VERSION 5.8 ;
BUSBITCHARS "[]" ;
DIVIDERCHAR "/" ;
UNITS
    DATABASE MICRONS 1000 ;
END UNITS

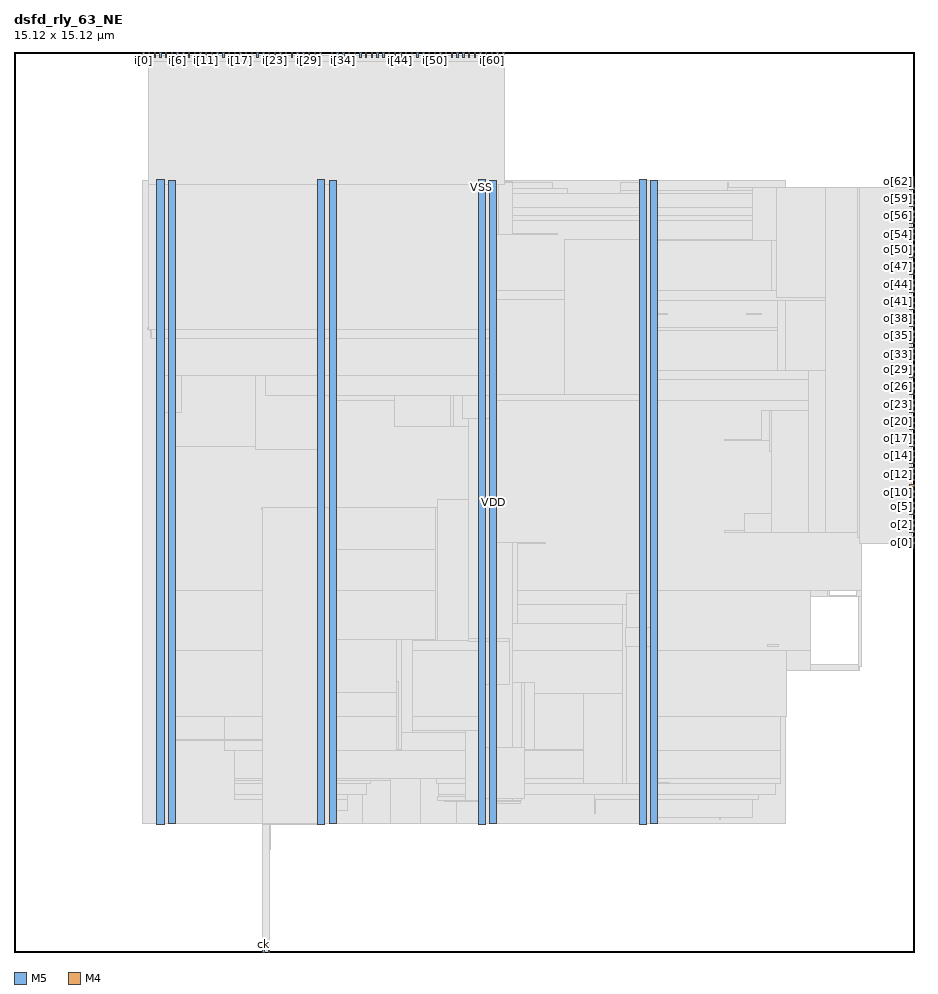
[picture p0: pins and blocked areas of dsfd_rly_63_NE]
MACRO dsfd_rly_63_NE
  FOREIGN dsfd_rly_63_NE 0 0 ;
  CLASS BLOCK ;
  SIZE 15.12 BY 15.12 ;
  PIN ck
    DIRECTION INPUT ;
    USE SIGNAL ;
    PORT
      LAYER M5 ;
        RECT  4.176 0 4.2 0.084 ;
    END
  END ck
  PIN i[0]
    DIRECTION INPUT ;
    USE SIGNAL ;
    PORT
      LAYER M5 ;
        RECT  2.16 15.036 2.184 15.12 ;
    END
  END i[0]
  PIN i[10]
    DIRECTION INPUT ;
    USE SIGNAL ;
    PORT
      LAYER M5 ;
        RECT  3.12 15.036 3.144 15.12 ;
    END
  END i[10]
  PIN i[11]
    DIRECTION INPUT ;
    USE SIGNAL ;
    PORT
      LAYER M5 ;
        RECT  3.216 15.036 3.24 15.12 ;
    END
  END i[11]
  PIN i[12]
    DIRECTION INPUT ;
    USE SIGNAL ;
    PORT
      LAYER M5 ;
        RECT  3.312 15.036 3.336 15.12 ;
    END
  END i[12]
  PIN i[13]
    DIRECTION INPUT ;
    USE SIGNAL ;
    PORT
      LAYER M5 ;
        RECT  3.408 15.036 3.432 15.12 ;
    END
  END i[13]
  PIN i[14]
    DIRECTION INPUT ;
    USE SIGNAL ;
    PORT
      LAYER M5 ;
        RECT  3.504 15.036 3.528 15.12 ;
    END
  END i[14]
  PIN i[15]
    DIRECTION INPUT ;
    USE SIGNAL ;
    PORT
      LAYER M5 ;
        RECT  3.6 15.036 3.624 15.12 ;
    END
  END i[15]
  PIN i[16]
    DIRECTION INPUT ;
    USE SIGNAL ;
    PORT
      LAYER M5 ;
        RECT  3.696 15.036 3.72 15.12 ;
    END
  END i[16]
  PIN i[17]
    DIRECTION INPUT ;
    USE SIGNAL ;
    PORT
      LAYER M5 ;
        RECT  3.792 15.036 3.816 15.12 ;
    END
  END i[17]
  PIN i[18]
    DIRECTION INPUT ;
    USE SIGNAL ;
    PORT
      LAYER M5 ;
        RECT  3.888 15.036 3.912 15.12 ;
    END
  END i[18]
  PIN i[19]
    DIRECTION INPUT ;
    USE SIGNAL ;
    PORT
      LAYER M5 ;
        RECT  3.984 15.036 4.008 15.12 ;
    END
  END i[19]
  PIN i[1]
    DIRECTION INPUT ;
    USE SIGNAL ;
    PORT
      LAYER M5 ;
        RECT  2.256 15.036 2.28 15.12 ;
    END
  END i[1]
  PIN i[20]
    DIRECTION INPUT ;
    USE SIGNAL ;
    PORT
      LAYER M5 ;
        RECT  4.08 15.036 4.104 15.12 ;
    END
  END i[20]
  PIN i[21]
    DIRECTION INPUT ;
    USE SIGNAL ;
    PORT
      LAYER M5 ;
        RECT  4.176 15.036 4.2 15.12 ;
    END
  END i[21]
  PIN i[22]
    DIRECTION INPUT ;
    USE SIGNAL ;
    PORT
      LAYER M5 ;
        RECT  4.272 15.036 4.296 15.12 ;
    END
  END i[22]
  PIN i[23]
    DIRECTION INPUT ;
    USE SIGNAL ;
    PORT
      LAYER M5 ;
        RECT  4.368 15.036 4.392 15.12 ;
    END
  END i[23]
  PIN i[24]
    DIRECTION INPUT ;
    USE SIGNAL ;
    PORT
      LAYER M5 ;
        RECT  4.464 15.036 4.488 15.12 ;
    END
  END i[24]
  PIN i[25]
    DIRECTION INPUT ;
    USE SIGNAL ;
    PORT
      LAYER M5 ;
        RECT  4.56 15.036 4.584 15.12 ;
    END
  END i[25]
  PIN i[26]
    DIRECTION INPUT ;
    USE SIGNAL ;
    PORT
      LAYER M5 ;
        RECT  4.656 15.036 4.68 15.12 ;
    END
  END i[26]
  PIN i[27]
    DIRECTION INPUT ;
    USE SIGNAL ;
    PORT
      LAYER M5 ;
        RECT  4.752 15.036 4.776 15.12 ;
    END
  END i[27]
  PIN i[28]
    DIRECTION INPUT ;
    USE SIGNAL ;
    PORT
      LAYER M5 ;
        RECT  4.848 15.036 4.872 15.12 ;
    END
  END i[28]
  PIN i[29]
    DIRECTION INPUT ;
    USE SIGNAL ;
    PORT
      LAYER M5 ;
        RECT  4.944 15.036 4.968 15.12 ;
    END
  END i[29]
  PIN i[2]
    DIRECTION INPUT ;
    USE SIGNAL ;
    PORT
      LAYER M5 ;
        RECT  2.352 15.036 2.376 15.12 ;
    END
  END i[2]
  PIN i[30]
    DIRECTION INPUT ;
    USE SIGNAL ;
    PORT
      LAYER M5 ;
        RECT  5.04 15.036 5.064 15.12 ;
    END
  END i[30]
  PIN i[31]
    DIRECTION INPUT ;
    USE SIGNAL ;
    PORT
      LAYER M5 ;
        RECT  5.136 15.036 5.16 15.12 ;
    END
  END i[31]
  PIN i[32]
    DIRECTION INPUT ;
    USE SIGNAL ;
    PORT
      LAYER M5 ;
        RECT  5.328 15.036 5.352 15.12 ;
    END
  END i[32]
  PIN i[33]
    DIRECTION INPUT ;
    USE SIGNAL ;
    PORT
      LAYER M5 ;
        RECT  5.424 15.036 5.448 15.12 ;
    END
  END i[33]
  PIN i[34]
    DIRECTION INPUT ;
    USE SIGNAL ;
    PORT
      LAYER M5 ;
        RECT  5.52 15.036 5.544 15.12 ;
    END
  END i[34]
  PIN i[35]
    DIRECTION INPUT ;
    USE SIGNAL ;
    PORT
      LAYER M5 ;
        RECT  5.616 15.036 5.64 15.12 ;
    END
  END i[35]
  PIN i[36]
    DIRECTION INPUT ;
    USE SIGNAL ;
    PORT
      LAYER M5 ;
        RECT  5.712 15.036 5.736 15.12 ;
    END
  END i[36]
  PIN i[37]
    DIRECTION INPUT ;
    USE SIGNAL ;
    PORT
      LAYER M5 ;
        RECT  5.808 15.036 5.832 15.12 ;
    END
  END i[37]
  PIN i[38]
    DIRECTION INPUT ;
    USE SIGNAL ;
    PORT
      LAYER M5 ;
        RECT  5.904 15.036 5.928 15.12 ;
    END
  END i[38]
  PIN i[39]
    DIRECTION INPUT ;
    USE SIGNAL ;
    PORT
      LAYER M5 ;
        RECT  6 15.036 6.024 15.12 ;
    END
  END i[39]
  PIN i[3]
    DIRECTION INPUT ;
    USE SIGNAL ;
    PORT
      LAYER M5 ;
        RECT  2.448 15.036 2.472 15.12 ;
    END
  END i[3]
  PIN i[40]
    DIRECTION INPUT ;
    USE SIGNAL ;
    PORT
      LAYER M5 ;
        RECT  6.096 15.036 6.12 15.12 ;
    END
  END i[40]
  PIN i[41]
    DIRECTION INPUT ;
    USE SIGNAL ;
    PORT
      LAYER M5 ;
        RECT  6.192 15.036 6.216 15.12 ;
    END
  END i[41]
  PIN i[42]
    DIRECTION INPUT ;
    USE SIGNAL ;
    PORT
      LAYER M5 ;
        RECT  6.288 15.036 6.312 15.12 ;
    END
  END i[42]
  PIN i[43]
    DIRECTION INPUT ;
    USE SIGNAL ;
    PORT
      LAYER M5 ;
        RECT  6.384 15.036 6.408 15.12 ;
    END
  END i[43]
  PIN i[44]
    DIRECTION INPUT ;
    USE SIGNAL ;
    PORT
      LAYER M5 ;
        RECT  6.48 15.036 6.504 15.12 ;
    END
  END i[44]
  PIN i[45]
    DIRECTION INPUT ;
    USE SIGNAL ;
    PORT
      LAYER M5 ;
        RECT  6.576 15.036 6.6 15.12 ;
    END
  END i[45]
  PIN i[46]
    DIRECTION INPUT ;
    USE SIGNAL ;
    PORT
      LAYER M5 ;
        RECT  6.672 15.036 6.696 15.12 ;
    END
  END i[46]
  PIN i[47]
    DIRECTION INPUT ;
    USE SIGNAL ;
    PORT
      LAYER M5 ;
        RECT  6.768 15.036 6.792 15.12 ;
    END
  END i[47]
  PIN i[48]
    DIRECTION INPUT ;
    USE SIGNAL ;
    PORT
      LAYER M5 ;
        RECT  6.864 15.036 6.888 15.12 ;
    END
  END i[48]
  PIN i[49]
    DIRECTION INPUT ;
    USE SIGNAL ;
    PORT
      LAYER M5 ;
        RECT  6.96 15.036 6.984 15.12 ;
    END
  END i[49]
  PIN i[4]
    DIRECTION INPUT ;
    USE SIGNAL ;
    PORT
      LAYER M5 ;
        RECT  2.544 15.036 2.568 15.12 ;
    END
  END i[4]
  PIN i[50]
    DIRECTION INPUT ;
    USE SIGNAL ;
    PORT
      LAYER M5 ;
        RECT  7.056 15.036 7.08 15.12 ;
    END
  END i[50]
  PIN i[51]
    DIRECTION INPUT ;
    USE SIGNAL ;
    PORT
      LAYER M5 ;
        RECT  7.152 15.036 7.176 15.12 ;
    END
  END i[51]
  PIN i[52]
    DIRECTION INPUT ;
    USE SIGNAL ;
    PORT
      LAYER M5 ;
        RECT  7.248 15.036 7.272 15.12 ;
    END
  END i[52]
  PIN i[53]
    DIRECTION INPUT ;
    USE SIGNAL ;
    PORT
      LAYER M5 ;
        RECT  7.344 15.036 7.368 15.12 ;
    END
  END i[53]
  PIN i[54]
    DIRECTION INPUT ;
    USE SIGNAL ;
    PORT
      LAYER M5 ;
        RECT  7.44 15.036 7.464 15.12 ;
    END
  END i[54]
  PIN i[55]
    DIRECTION INPUT ;
    USE SIGNAL ;
    PORT
      LAYER M5 ;
        RECT  7.536 15.036 7.56 15.12 ;
    END
  END i[55]
  PIN i[56]
    DIRECTION INPUT ;
    USE SIGNAL ;
    PORT
      LAYER M5 ;
        RECT  7.632 15.036 7.656 15.12 ;
    END
  END i[56]
  PIN i[57]
    DIRECTION INPUT ;
    USE SIGNAL ;
    PORT
      LAYER M5 ;
        RECT  7.728 15.036 7.752 15.12 ;
    END
  END i[57]
  PIN i[58]
    DIRECTION INPUT ;
    USE SIGNAL ;
    PORT
      LAYER M5 ;
        RECT  7.824 15.036 7.848 15.12 ;
    END
  END i[58]
  PIN i[59]
    DIRECTION INPUT ;
    USE SIGNAL ;
    PORT
      LAYER M5 ;
        RECT  7.92 15.036 7.944 15.12 ;
    END
  END i[59]
  PIN i[5]
    DIRECTION INPUT ;
    USE SIGNAL ;
    PORT
      LAYER M5 ;
        RECT  2.64 15.036 2.664 15.12 ;
    END
  END i[5]
  PIN i[60]
    DIRECTION INPUT ;
    USE SIGNAL ;
    PORT
      LAYER M5 ;
        RECT  8.016 15.036 8.04 15.12 ;
    END
  END i[60]
  PIN i[61]
    DIRECTION INPUT ;
    USE SIGNAL ;
    PORT
      LAYER M5 ;
        RECT  8.112 15.036 8.136 15.12 ;
    END
  END i[61]
  PIN i[62]
    DIRECTION INPUT ;
    USE SIGNAL ;
    PORT
      LAYER M5 ;
        RECT  8.208 15.036 8.232 15.12 ;
    END
  END i[62]
  PIN i[6]
    DIRECTION INPUT ;
    USE SIGNAL ;
    PORT
      LAYER M5 ;
        RECT  2.736 15.036 2.76 15.12 ;
    END
  END i[6]
  PIN i[7]
    DIRECTION INPUT ;
    USE SIGNAL ;
    PORT
      LAYER M5 ;
        RECT  2.832 15.036 2.856 15.12 ;
    END
  END i[7]
  PIN i[8]
    DIRECTION INPUT ;
    USE SIGNAL ;
    PORT
      LAYER M5 ;
        RECT  2.928 15.036 2.952 15.12 ;
    END
  END i[8]
  PIN i[9]
    DIRECTION INPUT ;
    USE SIGNAL ;
    PORT
      LAYER M5 ;
        RECT  3.024 15.036 3.048 15.12 ;
    END
  END i[9]
  PIN o[0]
    DIRECTION OUTPUT ;
    USE SIGNAL ;
    PORT
      LAYER M4 ;
        RECT  15.036 6.864 15.12 6.888 ;
    END
  END o[0]
  PIN o[10]
    DIRECTION OUTPUT ;
    USE SIGNAL ;
    PORT
      LAYER M4 ;
        RECT  15.036 7.824 15.12 7.848 ;
    END
  END o[10]
  PIN o[11]
    DIRECTION OUTPUT ;
    USE SIGNAL ;
    PORT
      LAYER M4 ;
        RECT  15.036 7.92 15.12 7.944 ;
    END
  END o[11]
  PIN o[12]
    DIRECTION OUTPUT ;
    USE SIGNAL ;
    PORT
      LAYER M4 ;
        RECT  15.036 8.016 15.12 8.04 ;
    END
  END o[12]
  PIN o[13]
    DIRECTION OUTPUT ;
    USE SIGNAL ;
    PORT
      LAYER M4 ;
        RECT  15.036 8.112 15.12 8.136 ;
    END
  END o[13]
  PIN o[14]
    DIRECTION OUTPUT ;
    USE SIGNAL ;
    PORT
      LAYER M4 ;
        RECT  15.036 8.208 15.12 8.232 ;
    END
  END o[14]
  PIN o[15]
    DIRECTION OUTPUT ;
    USE SIGNAL ;
    PORT
      LAYER M4 ;
        RECT  15.036 8.304 15.12 8.328 ;
    END
  END o[15]
  PIN o[16]
    DIRECTION OUTPUT ;
    USE SIGNAL ;
    PORT
      LAYER M4 ;
        RECT  15.036 8.4 15.12 8.424 ;
    END
  END o[16]
  PIN o[17]
    DIRECTION OUTPUT ;
    USE SIGNAL ;
    PORT
      LAYER M4 ;
        RECT  15.036 8.496 15.12 8.52 ;
    END
  END o[17]
  PIN o[18]
    DIRECTION OUTPUT ;
    USE SIGNAL ;
    PORT
      LAYER M4 ;
        RECT  15.036 8.592 15.12 8.616 ;
    END
  END o[18]
  PIN o[19]
    DIRECTION OUTPUT ;
    USE SIGNAL ;
    PORT
      LAYER M4 ;
        RECT  15.036 8.688 15.12 8.712 ;
    END
  END o[19]
  PIN o[1]
    DIRECTION OUTPUT ;
    USE SIGNAL ;
    PORT
      LAYER M4 ;
        RECT  15.036 6.96 15.12 6.984 ;
    END
  END o[1]
  PIN o[20]
    DIRECTION OUTPUT ;
    USE SIGNAL ;
    PORT
      LAYER M4 ;
        RECT  15.036 8.784 15.12 8.808 ;
    END
  END o[20]
  PIN o[21]
    DIRECTION OUTPUT ;
    USE SIGNAL ;
    PORT
      LAYER M4 ;
        RECT  15.036 8.88 15.12 8.904 ;
    END
  END o[21]
  PIN o[22]
    DIRECTION OUTPUT ;
    USE SIGNAL ;
    PORT
      LAYER M4 ;
        RECT  15.036 8.976 15.12 9 ;
    END
  END o[22]
  PIN o[23]
    DIRECTION OUTPUT ;
    USE SIGNAL ;
    PORT
      LAYER M4 ;
        RECT  15.036 9.072 15.12 9.096 ;
    END
  END o[23]
  PIN o[24]
    DIRECTION OUTPUT ;
    USE SIGNAL ;
    PORT
      LAYER M4 ;
        RECT  15.036 9.168 15.12 9.192 ;
    END
  END o[24]
  PIN o[25]
    DIRECTION OUTPUT ;
    USE SIGNAL ;
    PORT
      LAYER M4 ;
        RECT  15.036 9.264 15.12 9.288 ;
    END
  END o[25]
  PIN o[26]
    DIRECTION OUTPUT ;
    USE SIGNAL ;
    PORT
      LAYER M4 ;
        RECT  15.036 9.36 15.12 9.384 ;
    END
  END o[26]
  PIN o[27]
    DIRECTION OUTPUT ;
    USE SIGNAL ;
    PORT
      LAYER M4 ;
        RECT  15.036 9.456 15.12 9.48 ;
    END
  END o[27]
  PIN o[28]
    DIRECTION OUTPUT ;
    USE SIGNAL ;
    PORT
      LAYER M4 ;
        RECT  15.036 9.552 15.12 9.576 ;
    END
  END o[28]
  PIN o[29]
    DIRECTION OUTPUT ;
    USE SIGNAL ;
    PORT
      LAYER M4 ;
        RECT  15.036 9.648 15.12 9.672 ;
    END
  END o[29]
  PIN o[2]
    DIRECTION OUTPUT ;
    USE SIGNAL ;
    PORT
      LAYER M4 ;
        RECT  15.036 7.056 15.12 7.08 ;
    END
  END o[2]
  PIN o[30]
    DIRECTION OUTPUT ;
    USE SIGNAL ;
    PORT
      LAYER M4 ;
        RECT  15.036 9.744 15.12 9.768 ;
    END
  END o[30]
  PIN o[31]
    DIRECTION OUTPUT ;
    USE SIGNAL ;
    PORT
      LAYER M4 ;
        RECT  15.036 9.84 15.12 9.864 ;
    END
  END o[31]
  PIN o[32]
    DIRECTION OUTPUT ;
    USE SIGNAL ;
    PORT
      LAYER M4 ;
        RECT  15.036 9.936 15.12 9.96 ;
    END
  END o[32]
  PIN o[33]
    DIRECTION OUTPUT ;
    USE SIGNAL ;
    PORT
      LAYER M4 ;
        RECT  15.036 10.032 15.12 10.056 ;
    END
  END o[33]
  PIN o[34]
    DIRECTION OUTPUT ;
    USE SIGNAL ;
    PORT
      LAYER M4 ;
        RECT  15.036 10.128 15.12 10.152 ;
    END
  END o[34]
  PIN o[35]
    DIRECTION OUTPUT ;
    USE SIGNAL ;
    PORT
      LAYER M4 ;
        RECT  15.036 10.224 15.12 10.248 ;
    END
  END o[35]
  PIN o[36]
    DIRECTION OUTPUT ;
    USE SIGNAL ;
    PORT
      LAYER M4 ;
        RECT  15.036 10.32 15.12 10.344 ;
    END
  END o[36]
  PIN o[37]
    DIRECTION OUTPUT ;
    USE SIGNAL ;
    PORT
      LAYER M4 ;
        RECT  15.036 10.416 15.12 10.44 ;
    END
  END o[37]
  PIN o[38]
    DIRECTION OUTPUT ;
    USE SIGNAL ;
    PORT
      LAYER M4 ;
        RECT  15.036 10.512 15.12 10.536 ;
    END
  END o[38]
  PIN o[39]
    DIRECTION OUTPUT ;
    USE SIGNAL ;
    PORT
      LAYER M4 ;
        RECT  15.036 10.608 15.12 10.632 ;
    END
  END o[39]
  PIN o[3]
    DIRECTION OUTPUT ;
    USE SIGNAL ;
    PORT
      LAYER M4 ;
        RECT  15.036 7.152 15.12 7.176 ;
    END
  END o[3]
  PIN o[40]
    DIRECTION OUTPUT ;
    USE SIGNAL ;
    PORT
      LAYER M4 ;
        RECT  15.036 10.704 15.12 10.728 ;
    END
  END o[40]
  PIN o[41]
    DIRECTION OUTPUT ;
    USE SIGNAL ;
    PORT
      LAYER M4 ;
        RECT  15.036 10.8 15.12 10.824 ;
    END
  END o[41]
  PIN o[42]
    DIRECTION OUTPUT ;
    USE SIGNAL ;
    PORT
      LAYER M4 ;
        RECT  15.036 10.896 15.12 10.92 ;
    END
  END o[42]
  PIN o[43]
    DIRECTION OUTPUT ;
    USE SIGNAL ;
    PORT
      LAYER M4 ;
        RECT  15.036 10.992 15.12 11.016 ;
    END
  END o[43]
  PIN o[44]
    DIRECTION OUTPUT ;
    USE SIGNAL ;
    PORT
      LAYER M4 ;
        RECT  15.036 11.088 15.12 11.112 ;
    END
  END o[44]
  PIN o[45]
    DIRECTION OUTPUT ;
    USE SIGNAL ;
    PORT
      LAYER M4 ;
        RECT  15.036 11.184 15.12 11.208 ;
    END
  END o[45]
  PIN o[46]
    DIRECTION OUTPUT ;
    USE SIGNAL ;
    PORT
      LAYER M4 ;
        RECT  15.036 11.28 15.12 11.304 ;
    END
  END o[46]
  PIN o[47]
    DIRECTION OUTPUT ;
    USE SIGNAL ;
    PORT
      LAYER M4 ;
        RECT  15.036 11.376 15.12 11.4 ;
    END
  END o[47]
  PIN o[48]
    DIRECTION OUTPUT ;
    USE SIGNAL ;
    PORT
      LAYER M4 ;
        RECT  15.036 11.472 15.12 11.496 ;
    END
  END o[48]
  PIN o[49]
    DIRECTION OUTPUT ;
    USE SIGNAL ;
    PORT
      LAYER M4 ;
        RECT  15.036 11.568 15.12 11.592 ;
    END
  END o[49]
  PIN o[4]
    DIRECTION OUTPUT ;
    USE SIGNAL ;
    PORT
      LAYER M4 ;
        RECT  15.036 7.248 15.12 7.272 ;
    END
  END o[4]
  PIN o[50]
    DIRECTION OUTPUT ;
    USE SIGNAL ;
    PORT
      LAYER M4 ;
        RECT  15.036 11.664 15.12 11.688 ;
    END
  END o[50]
  PIN o[51]
    DIRECTION OUTPUT ;
    USE SIGNAL ;
    PORT
      LAYER M4 ;
        RECT  15.036 11.76 15.12 11.784 ;
    END
  END o[51]
  PIN o[52]
    DIRECTION OUTPUT ;
    USE SIGNAL ;
    PORT
      LAYER M4 ;
        RECT  15.036 11.856 15.12 11.88 ;
    END
  END o[52]
  PIN o[53]
    DIRECTION OUTPUT ;
    USE SIGNAL ;
    PORT
      LAYER M4 ;
        RECT  15.036 11.952 15.12 11.976 ;
    END
  END o[53]
  PIN o[54]
    DIRECTION OUTPUT ;
    USE SIGNAL ;
    PORT
      LAYER M4 ;
        RECT  15.036 12.048 15.12 12.072 ;
    END
  END o[54]
  PIN o[55]
    DIRECTION OUTPUT ;
    USE SIGNAL ;
    PORT
      LAYER M4 ;
        RECT  15.036 12.144 15.12 12.168 ;
    END
  END o[55]
  PIN o[56]
    DIRECTION OUTPUT ;
    USE SIGNAL ;
    PORT
      LAYER M4 ;
        RECT  15.036 12.24 15.12 12.264 ;
    END
  END o[56]
  PIN o[57]
    DIRECTION OUTPUT ;
    USE SIGNAL ;
    PORT
      LAYER M4 ;
        RECT  15.036 12.336 15.12 12.36 ;
    END
  END o[57]
  PIN o[58]
    DIRECTION OUTPUT ;
    USE SIGNAL ;
    PORT
      LAYER M4 ;
        RECT  15.036 12.432 15.12 12.456 ;
    END
  END o[58]
  PIN o[59]
    DIRECTION OUTPUT ;
    USE SIGNAL ;
    PORT
      LAYER M4 ;
        RECT  15.036 12.528 15.12 12.552 ;
    END
  END o[59]
  PIN o[5]
    DIRECTION OUTPUT ;
    USE SIGNAL ;
    PORT
      LAYER M4 ;
        RECT  15.036 7.344 15.12 7.368 ;
    END
  END o[5]
  PIN o[60]
    DIRECTION OUTPUT ;
    USE SIGNAL ;
    PORT
      LAYER M4 ;
        RECT  15.036 12.624 15.12 12.648 ;
    END
  END o[60]
  PIN o[61]
    DIRECTION OUTPUT ;
    USE SIGNAL ;
    PORT
      LAYER M4 ;
        RECT  15.036 12.72 15.12 12.744 ;
    END
  END o[61]
  PIN o[62]
    DIRECTION OUTPUT ;
    USE SIGNAL ;
    PORT
      LAYER M4 ;
        RECT  15.036 12.816 15.12 12.84 ;
    END
  END o[62]
  PIN o[6]
    DIRECTION OUTPUT ;
    USE SIGNAL ;
    PORT
      LAYER M4 ;
        RECT  15.036 7.44 15.12 7.464 ;
    END
  END o[6]
  PIN o[7]
    DIRECTION OUTPUT ;
    USE SIGNAL ;
    PORT
      LAYER M4 ;
        RECT  15.036 7.536 15.12 7.56 ;
    END
  END o[7]
  PIN o[8]
    DIRECTION OUTPUT ;
    USE SIGNAL ;
    PORT
      LAYER M4 ;
        RECT  15.036 7.632 15.12 7.656 ;
    END
  END o[8]
  PIN o[9]
    DIRECTION OUTPUT ;
    USE SIGNAL ;
    PORT
      LAYER M4 ;
        RECT  15.036 7.728 15.12 7.752 ;
    END
  END o[9]
  PIN rs
    DIRECTION INPUT ;
    USE SIGNAL ;
    PORT
      LAYER M5 ;
        RECT  4.272 0 4.296 0.084 ;
    END
  END rs
  PIN VDD
    DIRECTION INOUT ;
    USE POWER ;
    PORT
      LAYER M5 ;
        RECT  10.692 2.151 10.812 12.969 ;
        RECT  7.992 2.151 8.112 12.969 ;
        RECT  5.292 2.151 5.412 12.969 ;
        RECT  2.592 2.151 2.712 12.969 ;
    END
  END VDD
  PIN VSS
    DIRECTION INOUT ;
    USE GROUND ;
    PORT
      LAYER M5 ;
        RECT  10.5 2.137 10.62 12.983 ;
        RECT  7.8 2.137 7.92 12.983 ;
        RECT  5.1 2.137 5.22 12.983 ;
        RECT  2.4 2.137 2.52 12.983 ;
    END
  END VSS
  OBS
    LAYER RVTN ;
     RECT  2.16 2.16 12.96 2.295 ;
     RECT  2.16 2.565 12.96 2.835 ;
     RECT  2.16 3.105 12.96 3.375 ;
     RECT  2.16 3.645 12.96 3.915 ;
     RECT  2.16 4.185 12.96 4.455 ;
     RECT  2.16 4.725 12.96 4.995 ;
     RECT  2.16 5.265 12.96 5.535 ;
     RECT  2.16 5.805 12.96 6.075 ;
     RECT  2.16 6.345 12.96 6.615 ;
     RECT  2.16 6.885 12.96 7.155 ;
     RECT  2.16 7.425 12.96 7.695 ;
     RECT  2.16 7.965 12.96 8.235 ;
     RECT  2.16 8.505 12.96 8.775 ;
     RECT  2.16 9.045 12.96 9.315 ;
     RECT  2.16 9.585 12.96 9.855 ;
     RECT  2.16 10.125 12.96 10.395 ;
     RECT  2.16 10.665 12.96 10.935 ;
     RECT  2.16 11.205 12.96 11.475 ;
     RECT  2.16 11.745 12.96 12.015 ;
     RECT  2.16 12.285 12.96 12.555 ;
     RECT  2.16 12.825 12.96 12.96 ;
    LAYER RVTP ;
     RECT  2.16 2.295 12.96 2.565 ;
     RECT  2.16 2.835 12.96 3.105 ;
     RECT  2.16 3.375 12.96 3.645 ;
     RECT  2.16 3.915 12.96 4.185 ;
     RECT  2.16 4.455 12.96 4.725 ;
     RECT  2.16 4.995 12.96 5.265 ;
     RECT  2.16 5.535 12.96 5.805 ;
     RECT  2.16 6.075 12.96 6.345 ;
     RECT  2.16 6.615 12.96 6.885 ;
     RECT  2.16 7.155 12.96 7.425 ;
     RECT  2.16 7.695 12.96 7.965 ;
     RECT  2.16 8.235 12.96 8.505 ;
     RECT  2.16 8.775 12.96 9.045 ;
     RECT  2.16 9.315 12.96 9.585 ;
     RECT  2.16 9.855 12.96 10.125 ;
     RECT  2.16 10.395 12.96 10.665 ;
     RECT  2.16 10.935 12.96 11.205 ;
     RECT  2.16 11.475 12.96 11.745 ;
     RECT  2.16 12.015 12.96 12.285 ;
     RECT  2.16 12.555 12.96 12.825 ;
    LAYER M1 ;
     RECT  2.16 2.151 12.96 12.969 ;
    LAYER M2 ;
     RECT  2.16 2.151 5.863 12.969 ;
     RECT  5.863 2.151 6.331 13.014 ;
     RECT  6.331 2.151 6.827 13.05 ;
     RECT  6.827 2.151 7.439 13.014 ;
     RECT  7.439 2.151 12.96 12.969 ;
     RECT  12.96 3.96 12.983 3.978 ;
     RECT  12.96 4.734 13.379 5.094 ;
     RECT  12.96 5.976 13.667 12.744 ;
     RECT  13.667 5.976 13.703 6.102 ;
     RECT  13.703 5.976 14.171 5.994 ;
     RECT  13.379 4.734 14.207 4.824 ;
     RECT  13.667 7.281 14.207 12.744 ;
     RECT  14.207 4.806 14.243 4.824 ;
     RECT  14.207 7.281 14.243 9.882 ;
     RECT  14.207 10.791 14.243 12.744 ;
     RECT  14.243 9.09 14.279 9.882 ;
     RECT  14.243 7.398 15.035 7.416 ;
     RECT  14.279 9.09 15.035 9.684 ;
     RECT  14.243 10.872 15.035 10.89 ;
     RECT  14.243 12.456 15.035 12.474 ;
    LAYER M3 ;
     RECT  10.515 2.143 10.605 2.263 ;
     RECT  11.844 2.227 11.862 2.263 ;
     RECT  4.284 1.723 4.302 2.299 ;
     RECT  4.284 2.299 4.338 2.335 ;
     RECT  5.115 2.143 5.205 2.335 ;
     RECT  4.284 2.335 5.205 2.371 ;
     RECT  2.415 2.143 2.505 2.413 ;
     RECT  7.815 2.143 7.905 2.413 ;
     RECT  7.815 2.413 8.097 2.497 ;
     RECT  7.815 2.497 8.514 2.533 ;
     RECT  7.236 2.533 8.514 2.539 ;
     RECT  4.284 2.371 5.598 2.569 ;
     RECT  9.756 2.335 9.774 2.569 ;
     RECT  10.515 2.263 12.402 2.569 ;
     RECT  3.708 2.569 5.598 2.641 ;
     RECT  7.128 2.539 8.514 2.641 ;
     RECT  9.756 2.569 12.51 2.641 ;
     RECT  3.708 2.641 5.922 2.839 ;
     RECT  7.128 2.641 12.798 2.839 ;
     RECT  3.708 2.839 5.994 2.875 ;
     RECT  3.708 2.875 6.318 2.911 ;
     RECT  7.092 2.839 12.87 2.911 ;
     RECT  3.708 2.911 12.87 3.379 ;
     RECT  2.415 2.413 2.697 3.955 ;
     RECT  3.528 3.379 12.87 3.955 ;
     RECT  14.184 4.729 14.202 4.801 ;
     RECT  2.415 3.955 12.978 5.071 ;
     RECT  14.184 4.801 14.238 5.971 ;
     RECT  2.415 5.071 13.374 6.079 ;
     RECT  14.148 5.971 14.238 6.079 ;
     RECT  15.012 7.393 15.03 8.045 ;
     RECT  2.415 6.079 14.238 9.259 ;
     RECT  2.415 9.259 14.274 9.625 ;
     RECT  15.012 9.085 15.03 9.625 ;
     RECT  2.415 9.625 15.03 9.773 ;
     RECT  2.415 9.773 12.834 10.435 ;
     RECT  2.268 10.435 12.834 10.493 ;
     RECT  2.415 10.493 12.834 10.939 ;
     RECT  13.644 9.773 15.03 10.939 ;
     RECT  2.415 10.939 15.03 11.117 ;
     RECT  13.536 11.117 15.03 11.405 ;
     RECT  13.608 11.405 15.03 11.501 ;
     RECT  2.415 11.117 12.726 12.289 ;
     RECT  13.608 11.501 14.238 12.289 ;
     RECT  2.415 12.289 14.238 12.365 ;
     RECT  13.644 12.365 14.238 12.389 ;
     RECT  2.415 12.365 12.618 12.515 ;
     RECT  2.415 12.515 12.438 12.749 ;
     RECT  14.22 12.389 14.238 12.749 ;
     RECT  15.012 11.501 15.03 12.749 ;
     RECT  10.188 12.749 12.438 12.785 ;
     RECT  2.415 12.749 9.306 12.821 ;
     RECT  11.988 12.785 12.438 12.845 ;
     RECT  2.415 12.821 9.054 12.929 ;
     RECT  10.188 12.785 10.71 12.929 ;
     RECT  11.988 12.845 12.006 12.929 ;
     RECT  2.415 12.929 8.37 12.941 ;
     RECT  2.415 12.941 8.082 12.977 ;
     RECT  10.515 12.929 10.605 12.977 ;
     RECT  2.844 12.977 8.082 13.055 ;
     RECT  2.844 13.055 6.318 13.085 ;
     RECT  7.416 13.055 8.082 13.085 ;
     RECT  2.844 13.085 3.474 13.133 ;
     RECT  7.416 13.085 7.974 13.133 ;
     RECT  4.464 13.085 6.318 13.181 ;
     RECT  7.416 13.133 7.794 13.181 ;
     RECT  7.776 13.181 7.794 13.709 ;
     RECT  6.12 13.181 6.318 14.285 ;
     RECT  6.3 14.285 6.318 14.333 ;
     RECT  2.916 13.133 3.438 14.731 ;
     RECT  2.736 14.731 3.438 14.909 ;
     RECT  2.916 14.909 3.15 14.957 ;
     RECT  3.132 14.957 3.15 15.005 ;
     RECT  4.464 13.181 4.482 15.005 ;
    LAYER M4 ;
     RECT  2.245 10.464 2.293 10.488 ;
     RECT  2.149 14.976 2.293 15 ;
     RECT  2.293 10.32 2.408 10.488 ;
     RECT  2.408 2.148 2.512 12.972 ;
     RECT  2.512 2.418 2.533 12.972 ;
     RECT  2.293 14.832 2.629 15 ;
     RECT  2.533 2.418 2.704 13.128 ;
     RECT  2.629 14.64 2.867 15 ;
     RECT  2.867 14.88 3.161 15 ;
     RECT  3.161 14.88 3.449 14.952 ;
     RECT  2.704 12.528 3.485 13.128 ;
     RECT  3.485 12.528 3.949 13.08 ;
     RECT  2.704 8.496 4.057 10.824 ;
     RECT  3.449 14.928 4.259 14.952 ;
     RECT  4.229 1.728 4.313 1.752 ;
     RECT  4.453 14.976 4.595 15 ;
     RECT  3.949 12.336 4.705 13.08 ;
     RECT  4.705 12.288 5.029 13.08 ;
     RECT  5.029 12.24 5.093 13.128 ;
     RECT  2.704 3.552 5.108 3.576 ;
     RECT  4.417 6.144 5.108 6.168 ;
     RECT  4.165 7.44 5.108 7.464 ;
     RECT  4.057 8.448 5.108 10.824 ;
     RECT  5.093 12.24 5.108 13.176 ;
     RECT  5.108 2.148 5.212 13.176 ;
     RECT  5.212 2.418 5.404 13.176 ;
     RECT  5.404 9.36 5.557 13.176 ;
     RECT  5.557 9.36 5.795 13.224 ;
     RECT  5.795 9.36 6.149 12.936 ;
     RECT  6.109 14.256 6.289 14.28 ;
     RECT  6.149 9.36 6.397 10.824 ;
     RECT  5.404 4.368 6.421 5.256 ;
     RECT  6.289 14.256 6.469 14.328 ;
     RECT  6.421 3.408 6.508 5.256 ;
     RECT  6.469 14.16 6.611 14.328 ;
     RECT  6.508 3.696 6.689 5.256 ;
     RECT  6.689 5.232 7.081 5.256 ;
     RECT  5.404 6.768 7.081 7.464 ;
     RECT  7.081 5.232 7.117 7.464 ;
     RECT  6.397 8.832 7.333 10.824 ;
     RECT  7.333 8.832 7.388 10.968 ;
     RECT  6.149 12.48 7.388 12.936 ;
     RECT  6.611 14.304 7.571 14.328 ;
     RECT  7.117 2.544 7.585 2.616 ;
     RECT  6.689 3.696 7.585 3.72 ;
     RECT  7.388 12.48 7.765 13.176 ;
     RECT  7.585 2.544 7.808 3.72 ;
     RECT  7.117 5.232 7.808 7.608 ;
     RECT  7.388 8.832 7.808 11.16 ;
     RECT  7.765 12.48 7.808 13.704 ;
     RECT  7.808 2.148 7.912 13.704 ;
     RECT  7.912 2.418 8.051 13.704 ;
     RECT  8.051 2.418 8.104 13.08 ;
     RECT  8.104 12.048 8.147 13.08 ;
     RECT  8.104 2.544 8.381 6.888 ;
     RECT  8.147 12.048 8.381 12.936 ;
     RECT  8.381 5.52 8.453 6.888 ;
     RECT  8.381 2.544 8.525 4.536 ;
     RECT  8.525 2.592 8.579 4.536 ;
     RECT  8.579 3.408 8.741 4.536 ;
     RECT  8.453 6.864 8.921 6.888 ;
     RECT  8.381 12.048 9.137 12.072 ;
     RECT  8.104 9.36 9.241 10.968 ;
     RECT  8.741 3.408 9.565 4.344 ;
     RECT  9.565 2.832 10.22 4.344 ;
     RECT  8.453 5.52 10.22 5.832 ;
     RECT  10.22 2.832 10.285 5.832 ;
     RECT  10.285 2.832 10.508 6.024 ;
     RECT  9.241 9.36 10.508 11.976 ;
     RECT  10.508 2.148 10.612 12.972 ;
     RECT  10.612 2.418 10.804 12.702 ;
     RECT  10.804 10.704 10.973 10.728 ;
     RECT  10.804 2.832 11.009 2.856 ;
     RECT  11.941 7.056 12.265 7.08 ;
     RECT  10.804 11.952 12.409 11.976 ;
     RECT  11.941 8.592 12.553 8.616 ;
     RECT  12.301 10.704 12.557 10.728 ;
     RECT  12.553 8.592 12.697 9.096 ;
     RECT  12.265 7.056 12.733 7.368 ;
     RECT  12.697 8.4 12.733 9.096 ;
     RECT  12.409 11.952 12.805 12.84 ;
     RECT  12.661 5.136 12.845 5.16 ;
     RECT  12.733 7.056 13.345 9.096 ;
     RECT  13.345 7.056 13.633 9.768 ;
     RECT  12.805 10.992 13.633 12.84 ;
     RECT  13.633 7.056 14.173 12.84 ;
     RECT  14.173 6.96 14.209 12.84 ;
     RECT  14.209 6.864 15.084 12.84 ;
    LAYER M5 ;
     RECT  4.176 0.016 4.296 2.137 ;
     RECT  2.4 2.137 2.52 2.151 ;
     RECT  4.176 2.137 5.22 2.151 ;
     RECT  7.8 2.137 7.92 2.151 ;
     RECT  10.5 2.137 10.62 2.151 ;
     RECT  7.8 2.151 8.112 2.581 ;
     RECT  7.8 2.581 8.568 3.443 ;
     RECT  7.8 3.443 8.112 4.501 ;
     RECT  6.432 3.397 6.456 4.547 ;
     RECT  10.5 2.151 10.812 5.125 ;
     RECT  7.8 4.501 8.328 5.221 ;
     RECT  7.632 5.221 8.328 5.267 ;
     RECT  10.272 5.125 10.812 5.459 ;
     RECT  4.176 2.151 5.412 7.475 ;
     RECT  7.632 5.267 8.112 8.965 ;
     RECT  2.4 2.151 2.712 9.061 ;
     RECT  5.1 7.475 5.412 9.349 ;
     RECT  7.536 8.965 8.112 9.349 ;
     RECT  2.4 9.061 2.808 9.685 ;
     RECT  4.224 9.349 8.112 9.685 ;
     RECT  2.4 9.685 8.112 10.309 ;
     RECT  2.304 10.309 8.112 10.453 ;
     RECT  2.256 10.453 8.112 12.901 ;
     RECT  10.5 5.459 10.812 12.969 ;
     RECT  10.5 12.969 10.62 12.983 ;
     RECT  2.256 12.901 8.232 14.965 ;
     RECT  2.16 14.965 8.232 15.056 ;
  END
END dsfd_rly_63_NE
END LIBRARY
